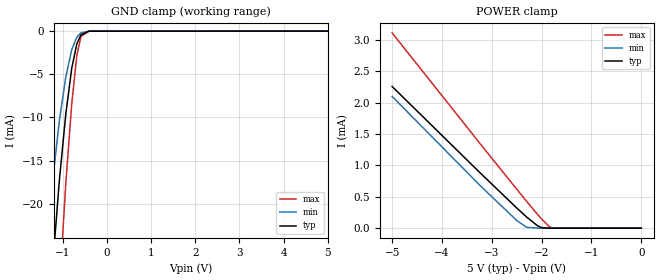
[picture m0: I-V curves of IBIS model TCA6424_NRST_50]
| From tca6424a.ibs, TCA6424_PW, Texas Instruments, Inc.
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[Model]   TCA6424_NRST_50
Model_type  Input
Vinl=1.35
Vinh=3.85
| variable   typ   min   max
C_comp   2.17pF   1.80pF   2.32pF
[Temperature Range]   40   100   -40
| Ambient temperature   25   85   -40
[Voltage range]   5   4.5   5.5
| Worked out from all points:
|   GND clamp passes 1 mA (typ) near -0.65 V on its own axis
|   POWER clamp passes 1 mA (typ) near -3.39 V on its own axis
[GND Clamp]
| TCA6424_NRST_50
|   Voltage   I(typ)   I(min)   I(max)
-5V       -421.5mA   -327.2mA   -555.2mA
-1.48V    -46.19mA   -30.98mA   -72.79mA
-1.435V   -42.57mA   -28.34mA   -67.61mA
-1.265V   -29.76mA   -19.1mA    -48.89mA
-1.085V   -17.96mA   -10.85mA   -30.98mA
-1.065V   -16.78mA   -10.05mA   -29.14mA
-930mV    -9.662mA   -5.357mA   -17.73mA
-795mV    -4.307mA   -2.154mA   -8.462mA
-680mV    -1.498mA   -708.4uA   -2.836mA
-585mV    -416.3uA   -213.5uA   -615.5uA
-405mV    -11.9uA    -9.596uA   -9.604uA
5V        572.5pA    2.003nA    91.86pA
[POWER Clamp]
| TCA6424_NRST_50
|   Voltage   I(typ)   I(min)   I(max)
-5V       2.259mA    2.101mA    3.114mA
-3.24V    886.3uA    684.1uA    1.353mA
-2.49V    314.9uA    114.8uA    611.7uA
-2.3V     176.9uA    14.07uA    427.1uA
-2.08V    36.49uA    30.1nA     218.5uA
-1.99V    5.536uA    5.854nA    137uA
-1.86V    59.38nA    4.002nA    34.02uA
-1.805V   9.042nA    3.854nA    7.955uA
-1.735V   1.991nA    3.696nA    355.1nA
-84.45fV  572.5pA    1.628nA    108.3pA
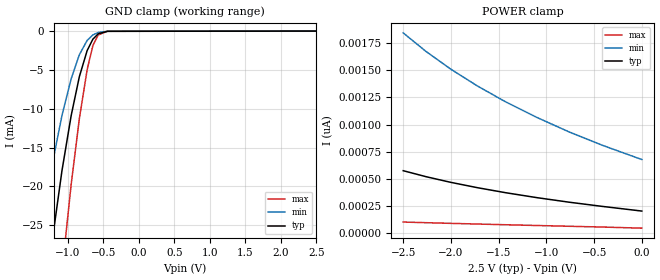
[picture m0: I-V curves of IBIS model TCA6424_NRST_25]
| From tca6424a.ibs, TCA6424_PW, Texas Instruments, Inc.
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[Model]   TCA6424_NRST_25
Model_type  Input
Vinl=0.69
Vinh=1.89
| variable   typ   min   max
C_comp   2.23pF   1.74pF   2.48pF
[Temperature Range]   40   100   -40
| Ambient temperature   25   85   -40
[Voltage range]   2.5   2.3   2.7
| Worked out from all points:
|   GND clamp passes 1 mA (typ) near -0.65 V on its own axis
[GND Clamp]
| TCA6424_NRST_25
|   Voltage   I(typ)   I(min)   I(max)
-2.5V     -143.4mA   -105mA     -204.1mA
-1.49V    -47mA      -31.57mA   -73.96mA
-1.46V    -44.57mA   -29.79mA   -70.48mA
-1.27V    -30.12mA   -19.36mA   -49.42mA
-1.085V   -17.96mA   -10.85mA   -30.98mA
-955mV    -10.86mA   -6.122mA   -19.7mA
-840mV    -5.866mA   -3.039mA   -11.27mA
-730mV    -2.504mA   -1.201mA   -4.956mA
-650mV    -1.048mA   -498.6uA   -1.878mA
-575mV    -354.2uA   -185.5uA   -505.4uA
-445mV    -29.23uA   -21.62uA   -27.21uA
2.5V      205.9pA    741.4pA    43.26pA
[POWER Clamp]
| TCA6424_NRST_25
|   Voltage   I(typ)   I(min)   I(max)
-2.5V     576.6pA    1.842nA    105.1pA
-2.26V    521.5pA    1.671nA    99.15pA
-2.005V   470.3pA    1.511nA    93.15pA
-1.725V   421pA      1.356nA    86.8pA
-1.425V   374.2pA    1.208nA    80.23pA
-1.1V     329.2pA    1.066nA    73.31pA
-760mV    287.2pA    932pA      66.26pA
-415mV    248.9pA    810.6pA    59.25pA
-31.15fV  205.9pA    679.1pA    48.93pA
